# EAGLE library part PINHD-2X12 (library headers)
PIN HEADER

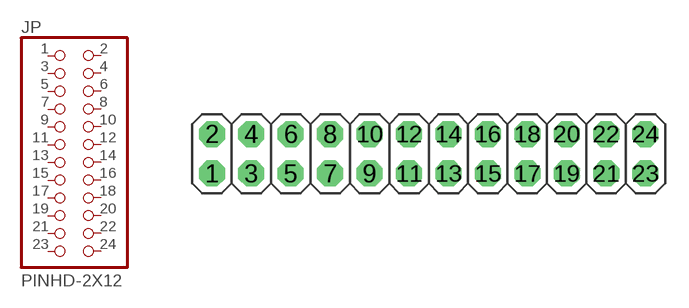
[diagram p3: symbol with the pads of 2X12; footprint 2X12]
Designator prefix JP

## PINHD-2X12  [2X12]
1  1  pas
2  2  pas
3  3  pas
4  4  pas
5  5  pas
6  6  pas
7  7  pas
8  8  pas
9  9  pas
10  10  pas
11  11  pas
12  12  pas
13  13  pas
14  14  pas
15  15  pas
16  16  pas
17  17  pas
18  18  pas
19  19  pas
20  20  pas
21  21  pas
22  22  pas
23  23  pas
24  24  pas

## Footprint 2X12 (pad centres in mm)
drill 1.016 pad 1.676 octagon: 1 -12.7,1.27; 2 -12.7,3.81; 3 -10.16,1.27; 4 -10.16,3.81; 5 -7.62,1.27; 6 -7.62,3.81; 7 -5.08,1.27; 8 -5.08,3.81; 9 -2.54,1.27; 10 -2.54,3.81; 11 0,1.27; 12 0,3.81; 13 2.54,1.27; 14 2.54,3.81; 15 5.08,1.27; 16 5.08,3.81; 17 7.62,1.27; 18 7.62,3.81; 19 10.16,1.27; 20 10.16,3.81; 21 12.7,1.27; 22 12.7,3.81; 23 15.24,1.27; 24 15.24,3.81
